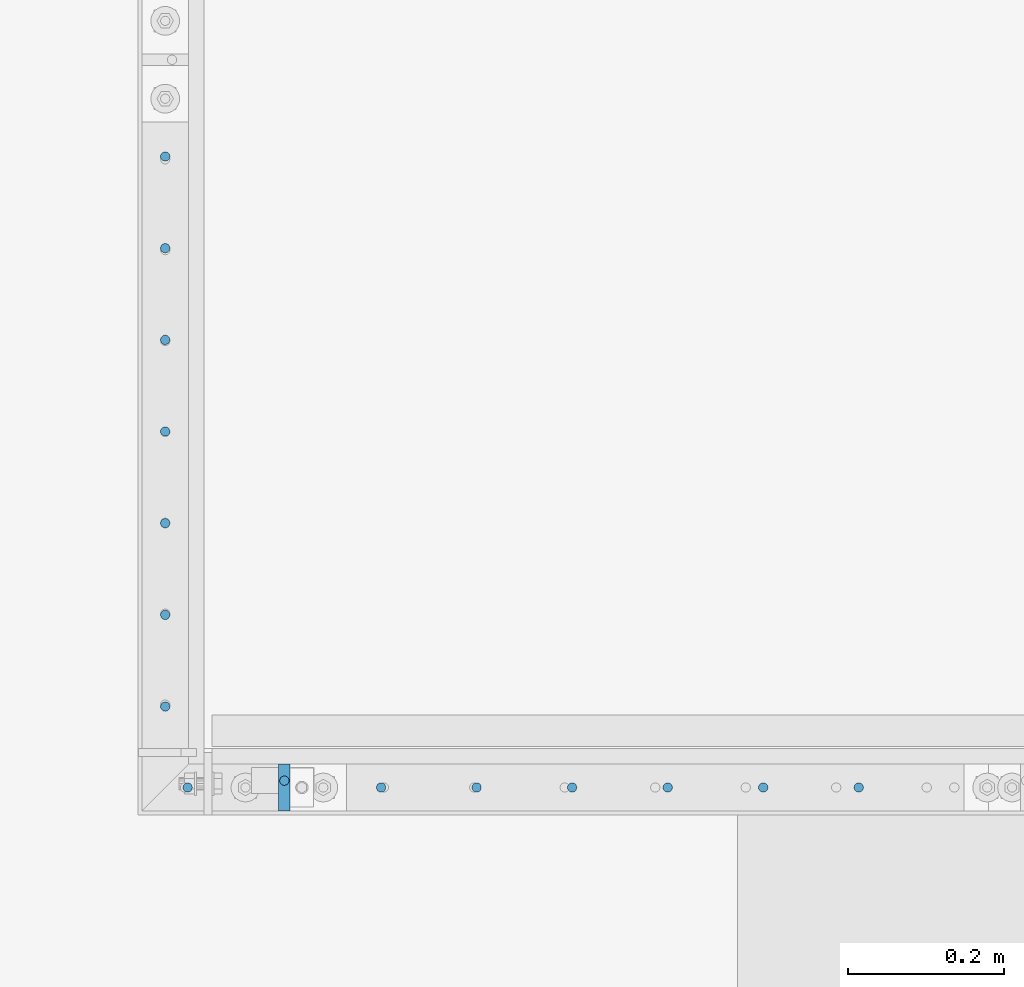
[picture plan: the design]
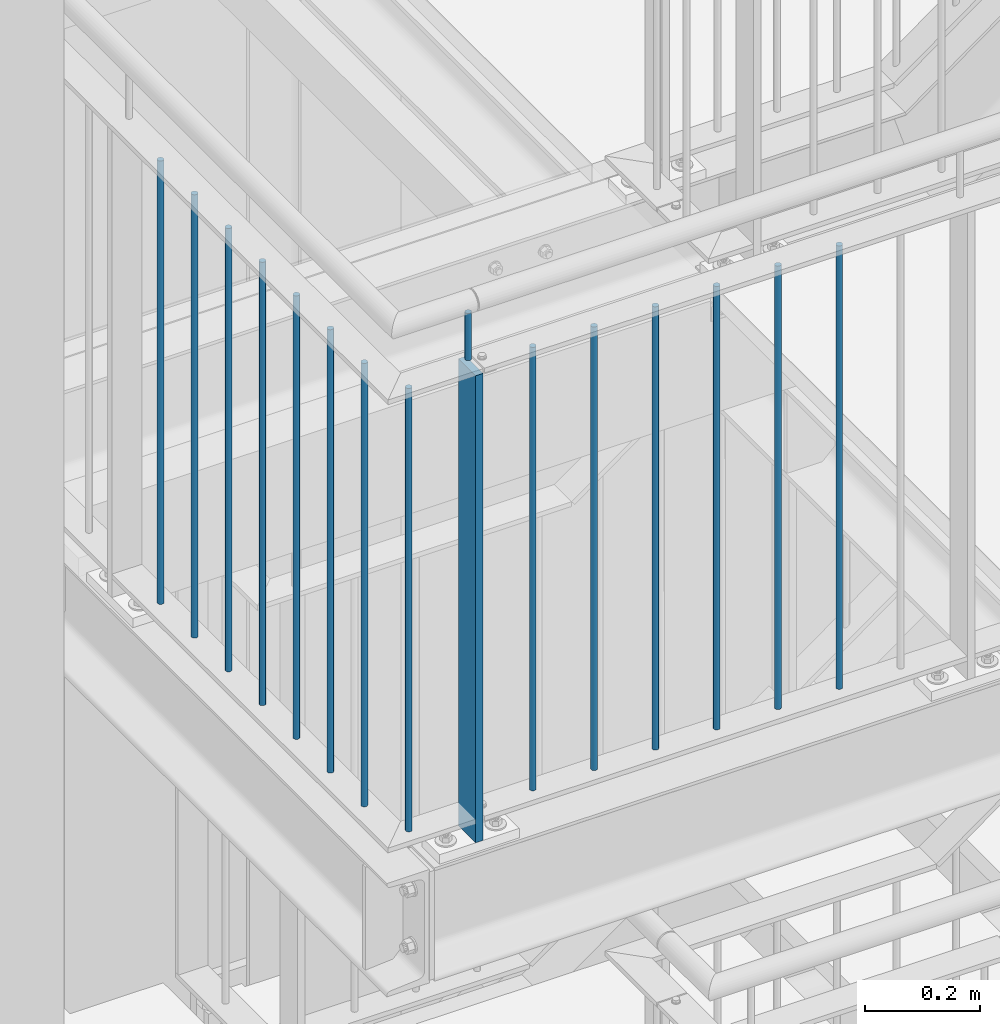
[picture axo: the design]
# One storey, part 7 of 831: 16 columns.
"""IFC2X3 building model written with IfcOpenShell, lengths in millimetres."""

from ifc_helpers import new_model, entity, si_unit, converted_unit, frame, origin, origin_with_axes, origin_2d, place, context, project, spatial, rectangle, circle, extrude, clip, halfspace, material, element, save


model = new_model("IFC2X3")

# Units and contexts
model_context = context("Model", 3, precision=1e-09, world=origin_with_axes())
ifc_project = project(units=[si_unit("LENGTHUNIT", "METRE", prefix="MILLI"), si_unit("AREAUNIT", "SQUARE_METRE"), si_unit("VOLUMEUNIT", "CUBIC_METRE"), converted_unit("PLANEANGLEUNIT", "DEGREE", entity("IfcPlaneAngleMeasure", 0.01745329), si_unit("PLANEANGLEUNIT", "RADIAN"), dimensions=[0, 0, 0, 0, 0, 0, 0])], contexts=[model_context])

# Site, building, storey
site_placement = place(None, origin_with_axes())
site = spatial("IfcSite", under=ifc_project, at=site_placement, CompositionType="ELEMENT")
building_placement = place(site_placement, origin_with_axes())
building = spatial("IfcBuilding", under=site, at=building_placement, Name="1", CompositionType="ELEMENT")
storey_placement = place(building_placement, origin_with_axes())
storey = spatial("IfcBuildingStorey", under=building, at=storey_placement, Name="Default Storey", CompositionType="ELEMENT", Elevation=0.0)

# Columns
ifc_material = material(Name="S235JR")
column_1_placement = place(None, frame((4162.791664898, 4526.736971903, 10974.285281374), z_axis=(0.0, 0.0, 1.0), x_axis=(-1.0, 0.0, 0.0)))
element("IfcColumn", 1, at=column_1_placement, inside=storey, material=ifc_material, Name="Railing_Picket_Landing#84", ObjectType="Railing_Picket_Landing#84", context=model_context, shape_type="Clipping", body=[
    clip(clip(extrude(circle(Radius=6.0, at=origin_2d()), origin(), (0.0, 0.0, -1.0), 965.770562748), halfspace(frame((4162.791664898, 4526.736971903, -13.486281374), z_axis=(0.0, 0.0, -1.0), x_axis=(1.0, 0.0, 0.0)), True)), halfspace(frame((4162.791664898, 4526.736971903, -952.284281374), z_axis=(0.0, 0.0, 1.0), x_axis=(-1.0, 0.0, 0.0)), True)),
])
column_2_placement = place(None, frame((4040.041641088, 4526.736971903, 10974.285281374), z_axis=(0.0, 0.0, 1.0), x_axis=(-1.0, 0.0, 0.0)))
element("IfcColumn", 2, at=column_2_placement, inside=storey, material=ifc_material, Name="Railing_Picket_Landing#85", ObjectType="Railing_Picket_Landing#85", context=model_context, shape_type="Clipping", body=[
    clip(clip(extrude(circle(Radius=6.0, at=origin_2d()), origin(), (0.0, 0.0, -1.0), 965.770562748), halfspace(frame((4040.041641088, 4526.736971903, -13.486281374), z_axis=(0.0, 0.0, -1.0), x_axis=(1.0, 0.0, 0.0)), True)), halfspace(frame((4040.041641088, 4526.736971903, -952.284281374), z_axis=(0.0, 0.0, 1.0), x_axis=(-1.0, 0.0, 0.0)), True)),
])
column_3_placement = place(None, frame((3917.291617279, 4526.736971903, 10974.285281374), z_axis=(0.0, 0.0, 1.0), x_axis=(-1.0, 0.0, 0.0)))
element("IfcColumn", 3, at=column_3_placement, inside=storey, material=ifc_material, Name="Railing_Picket_Landing#86", ObjectType="Railing_Picket_Landing#86", context=model_context, shape_type="Clipping", body=[
    clip(clip(extrude(circle(Radius=6.0, at=origin_2d()), origin(), (0.0, 0.0, -1.0), 965.770562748), halfspace(frame((3917.291617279, 4526.736971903, -13.486281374), z_axis=(0.0, 0.0, -1.0), x_axis=(1.0, 0.0, 0.0)), True)), halfspace(frame((3917.291617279, 4526.736971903, -952.284281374), z_axis=(0.0, 0.0, 1.0), x_axis=(-1.0, 0.0, 0.0)), True)),
])
column_4_placement = place(None, frame((3794.541593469, 4526.736971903, 10974.285281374), z_axis=(0.0, 0.0, 1.0), x_axis=(-1.0, 0.0, 0.0)))
element("IfcColumn", 4, at=column_4_placement, inside=storey, material=ifc_material, Name="Railing_Picket_Landing#87", ObjectType="Railing_Picket_Landing#87", context=model_context, shape_type="Clipping", body=[
    clip(clip(extrude(circle(Radius=6.0, at=origin_2d()), origin(), (0.0, 0.0, -1.0), 965.770562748), halfspace(frame((3794.541593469, 4526.736971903, -13.486281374), z_axis=(0.0, 0.0, -1.0), x_axis=(1.0, 0.0, 0.0)), True)), halfspace(frame((3794.541593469, 4526.736971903, -952.284281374), z_axis=(0.0, 0.0, 1.0), x_axis=(-1.0, 0.0, 0.0)), True)),
])
column_5_placement = place(None, frame((3671.79156966, 4526.736971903, 10974.285281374), z_axis=(0.0, 0.0, 1.0), x_axis=(-1.0, 0.0, 0.0)))
element("IfcColumn", 5, at=column_5_placement, inside=storey, material=ifc_material, Name="Railing_Picket_Landing#88", ObjectType="Railing_Picket_Landing#88", context=model_context, shape_type="Clipping", body=[
    clip(clip(extrude(circle(Radius=6.0, at=origin_2d()), origin(), (0.0, 0.0, -1.0), 965.770562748), halfspace(frame((3671.79156966, 4526.736971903, -13.486281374), z_axis=(0.0, 0.0, -1.0), x_axis=(1.0, 0.0, 0.0)), True)), halfspace(frame((3671.79156966, 4526.736971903, -952.284281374), z_axis=(0.0, 0.0, 1.0), x_axis=(-1.0, 0.0, 0.0)), True)),
])
column_6_placement = place(None, frame((3549.04154585, 4526.736971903, 10974.285281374), z_axis=(0.0, 0.0, 1.0), x_axis=(-1.0, 0.0, 0.0)))
element("IfcColumn", 6, at=column_6_placement, inside=storey, material=ifc_material, Name="Railing_Picket_Landing#89", ObjectType="Railing_Picket_Landing#89", context=model_context, shape_type="Clipping", body=[
    clip(clip(extrude(circle(Radius=6.0, at=origin_2d()), origin(), (0.0, 0.0, -1.0), 965.770562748), halfspace(frame((3549.04154585, 4526.736971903, -13.486281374), z_axis=(0.0, 0.0, -1.0), x_axis=(1.0, 0.0, 0.0)), True)), halfspace(frame((3549.04154585, 4526.736971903, -952.284281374), z_axis=(0.0, 0.0, 1.0), x_axis=(-1.0, 0.0, 0.0)), True)),
])
column_7_placement = place(None, frame((3300.54154585, 4526.736971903, 10974.285281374), z_axis=(0.0, 0.0, 1.0), x_axis=(-1.0, 0.0, 0.0)))
element("IfcColumn", 7, at=column_7_placement, inside=storey, material=ifc_material, Name="Railing_Picket_Landing#90", ObjectType="Railing_Picket_Landing#90", context=model_context, shape_type="Clipping", body=[
    clip(clip(extrude(circle(Radius=6.0, at=origin_2d()), origin(), (0.0, 0.0, -1.0), 965.770562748), halfspace(frame((3300.54154585, 4526.736971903, -13.486281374), z_axis=(0.0, 0.0, -1.0), x_axis=(1.0, 0.0, 0.0)), True)), halfspace(frame((3300.54154585, 4526.736971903, -952.284281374), z_axis=(0.0, 0.0, 1.0), x_axis=(-1.0, 0.0, 0.0)), True)),
])
column_8_placement = place(None, frame((3271.713402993, 4630.705992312, 10974.285281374), z_axis=(0.0, 0.0, 1.0), x_axis=(0.0, 1.0, 0.0)))
element("IfcColumn", 8, at=column_8_placement, inside=storey, material=ifc_material, Name="Railing_Picket_Landing#91", ObjectType="Railing_Picket_Landing#91", context=model_context, shape_type="Clipping", body=[
    clip(clip(extrude(circle(Radius=6.0, at=origin_2d()), origin(), (0.0, 0.0, -1.0), 965.770562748), halfspace(frame((-4630.705992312, 3271.713402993, -13.486281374), z_axis=(0.0, 0.0, -1.0), x_axis=(0.0, 1.0, 0.0)), True)), halfspace(frame((-4630.705992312, 3271.713402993, -952.284281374), z_axis=(0.0, 0.0, 1.0), x_axis=(0.0, -1.0, 0.0)), True)),
])
column_9_placement = place(None, frame((3271.713402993, 4748.503155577, 10974.285281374), z_axis=(0.0, 0.0, 1.0), x_axis=(0.0, 1.0, 0.0)))
element("IfcColumn", 9, at=column_9_placement, inside=storey, material=ifc_material, Name="Railing_Picket_Landing#92", ObjectType="Railing_Picket_Landing#92", context=model_context, shape_type="Clipping", body=[
    clip(clip(extrude(circle(Radius=6.0, at=origin_2d()), origin(), (0.0, 0.0, -1.0), 965.770562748), halfspace(frame((-4748.503155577, 3271.713402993, -13.486281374), z_axis=(0.0, 0.0, -1.0), x_axis=(0.0, 1.0, 0.0)), True)), halfspace(frame((-4748.503155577, 3271.713402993, -952.284281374), z_axis=(0.0, 0.0, 1.0), x_axis=(0.0, -1.0, 0.0)), True)),
])
column_10_placement = place(None, frame((3271.713402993, 4866.300318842, 10974.285281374), z_axis=(0.0, 0.0, 1.0), x_axis=(0.0, 1.0, 0.0)))
element("IfcColumn", 10, at=column_10_placement, inside=storey, material=ifc_material, Name="Railing_Picket_Landing#93", ObjectType="Railing_Picket_Landing#93", context=model_context, shape_type="Clipping", body=[
    clip(clip(extrude(circle(Radius=6.0, at=origin_2d()), origin(), (0.0, 0.0, -1.0), 965.770562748), halfspace(frame((-4866.300318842, 3271.713402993, -13.486281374), z_axis=(0.0, 0.0, -1.0), x_axis=(0.0, 1.0, 0.0)), True)), halfspace(frame((-4866.300318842, 3271.713402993, -952.284281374), z_axis=(0.0, 0.0, 1.0), x_axis=(0.0, -1.0, 0.0)), True)),
])
column_11_placement = place(None, frame((3271.713402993, 4984.097482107, 10974.285281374), z_axis=(0.0, 0.0, 1.0), x_axis=(0.0, 1.0, 0.0)))
element("IfcColumn", 11, at=column_11_placement, inside=storey, material=ifc_material, Name="Railing_Picket_Landing#94", ObjectType="Railing_Picket_Landing#94", context=model_context, shape_type="Clipping", body=[
    clip(clip(extrude(circle(Radius=6.0, at=origin_2d()), origin(), (0.0, 0.0, -1.0), 965.770562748), halfspace(frame((-4984.097482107, 3271.713402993, -13.486281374), z_axis=(0.0, 0.0, -1.0), x_axis=(0.0, 1.0, 0.0)), True)), halfspace(frame((-4984.097482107, 3271.713402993, -952.284281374), z_axis=(0.0, 0.0, 1.0), x_axis=(0.0, -1.0, 0.0)), True)),
])
column_12_placement = place(None, frame((3271.713402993, 5101.894645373, 10974.285281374), z_axis=(0.0, 0.0, 1.0), x_axis=(0.0, 1.0, 0.0)))
element("IfcColumn", 12, at=column_12_placement, inside=storey, material=ifc_material, Name="Railing_Picket_Landing#95", ObjectType="Railing_Picket_Landing#95", context=model_context, shape_type="Clipping", body=[
    clip(clip(extrude(circle(Radius=6.0, at=origin_2d()), origin(), (0.0, 0.0, -1.0), 965.770562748), halfspace(frame((-5101.894645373, 3271.713402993, -13.486281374), z_axis=(0.0, 0.0, -1.0), x_axis=(0.0, 1.0, 0.0)), True)), halfspace(frame((-5101.894645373, 3271.713402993, -952.284281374), z_axis=(0.0, 0.0, 1.0), x_axis=(0.0, -1.0, 0.0)), True)),
])
column_13_placement = place(None, frame((3271.713402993, 5219.691808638, 10974.285281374), z_axis=(0.0, 0.0, 1.0), x_axis=(0.0, 1.0, 0.0)))
element("IfcColumn", 13, at=column_13_placement, inside=storey, material=ifc_material, Name="Railing_Picket_Landing#96", ObjectType="Railing_Picket_Landing#96", context=model_context, shape_type="Clipping", body=[
    clip(clip(extrude(circle(Radius=6.0, at=origin_2d()), origin(), (0.0, 0.0, -1.0), 965.770562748), halfspace(frame((-5219.691808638, 3271.713402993, -13.486281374), z_axis=(0.0, 0.0, -1.0), x_axis=(0.0, 1.0, 0.0)), True)), halfspace(frame((-5219.691808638, 3271.713402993, -952.284281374), z_axis=(0.0, 0.0, 1.0), x_axis=(0.0, -1.0, 0.0)), True)),
])
column_14_placement = place(None, frame((3271.713402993, 5337.488971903, 10974.285281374), z_axis=(0.0, 0.0, 1.0), x_axis=(0.0, 1.0, 0.0)))
element("IfcColumn", 14, at=column_14_placement, inside=storey, material=ifc_material, Name="Railing_Picket_Landing#97", ObjectType="Railing_Picket_Landing#97", context=model_context, shape_type="Clipping", body=[
    clip(clip(extrude(circle(Radius=6.0, at=origin_2d()), origin(), (0.0, 0.0, -1.0), 965.770562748), halfspace(frame((-5337.488971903, 3271.713402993, -13.486281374), z_axis=(0.0, 0.0, -1.0), x_axis=(0.0, 1.0, 0.0)), True)), halfspace(frame((-5337.488971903, 3271.713402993, -952.284281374), z_axis=(0.0, 0.0, 1.0), x_axis=(0.0, -1.0, 0.0)), True)),
])
column_15_placement = place(None, frame((3424.79154585, 4535.536971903, 11079.285281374), z_axis=(0.0, 0.0, 1.0), x_axis=(0.0, 1.0, 0.0)))
element("IfcColumn", 15, at=column_15_placement, inside=storey, material=ifc_material, Name="Bar#13", ObjectType="Bar#13", context=model_context, shape_type="Clipping", body=[
    clip(clip(extrude(circle(Radius=6.0, at=origin_2d()), origin(), (0.0, 0.0, -1.0), 116.970562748), halfspace(frame((-4535.536971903, 3424.79154585, -8.486281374), z_axis=(0.0, 0.0, -1.0), x_axis=(0.0, 1.0, 0.0)), True)), halfspace(frame((-4535.536971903, 3424.79154585, -108.484281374), z_axis=(0.0, 0.0, 1.0), x_axis=(0.0, -1.0, 0.0)), True)),
])
column_16_placement = place(None, frame((3424.79154585, 4526.736971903, 10991.723292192), z_axis=(0.0, 0.0, 1.0), x_axis=(-1.0, 0.0, 0.0)))
element("IfcColumn", 16, at=column_16_placement, inside=storey, material=ifc_material, Name="Railing_Post_Landing#13", ObjectType="Railing_Post_Landing#13", context=model_context, shape_type="Clipping", body=[
    clip(clip(extrude(rectangle(XDim=15.0, YDim=60.0, at=origin_2d()), origin(), (0.0, 0.0, -1.0), 1070.646584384), halfspace(frame((3424.79154585, 4526.736971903, -1019.722292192), z_axis=(0.0, 0.0, 1.0), x_axis=(-1.0, 0.0, 0.0)), True)), halfspace(frame((3424.79154585, 4526.736971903, -30.924292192), z_axis=(0.0, 0.0, -1.0), x_axis=(1.0, 0.0, 0.0)), True)),
])

save(model, "model.ifc")
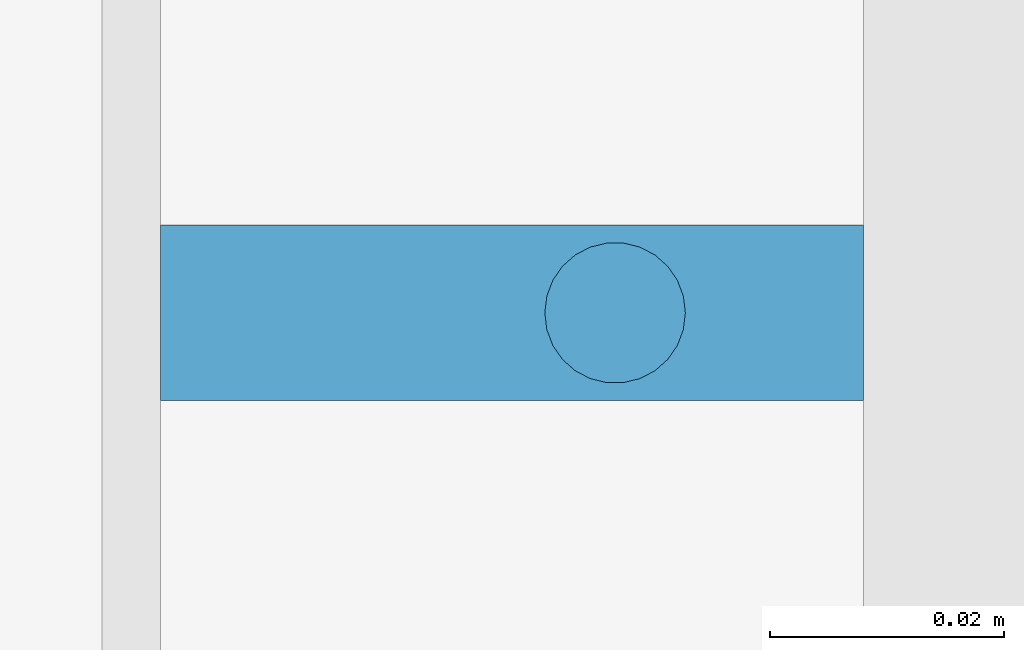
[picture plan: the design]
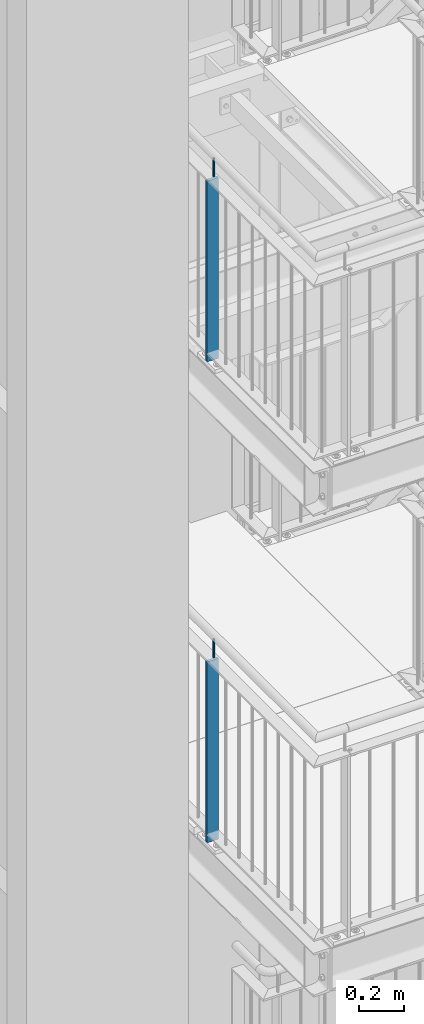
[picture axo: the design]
# One storey, part 18 of 831: 4 columns.
"""IFC2X3 building model written with IfcOpenShell, lengths in millimetres."""

import ifcopenshell
import ifcopenshell.guid

model = None  # the IFC model being written
_history = None  # IfcOwnerHistory: only IFC2X3 demands one
_inside = {}  # id of a spatial element -> (the spatial element, [elements in it])
_under = {}  # id of a project, library or spatial element -> (it, [spatial elements below it])
_declared = {}  # id of a project -> (the project, [libraries it declares])
_typed = {}  # id of a type object -> (the type object, [elements of that type])
_made_of = {}  # id of a material, layer set ... -> (it, [elements and type objects made of it])


def new_model(schema):
    """Start an empty IFC model of exactly this schema.

    Asked for "IFC4X3", IfcOpenShell would pick the latest addendum, in which some entities
    have other attributes; the version numbers below select the first issue.
    IFC2X3 requires an IfcOwnerHistory on every rooted entity: one is made here for all.
    """
    global model, _history
    if schema == "IFC4X3":
        model = ifcopenshell.file(schema_version=(4, 3, 0, 0))
    else:
        model = ifcopenshell.file(schema=schema)
    _inside.clear()
    _under.clear()
    _declared.clear()
    _typed.clear()
    _made_of.clear()
    _history = None
    if model.schema == "IFC2X3":
        org = make("IfcOrganization", Name="unknown")
        user = make(
            "IfcPersonAndOrganization",
            ThePerson=make("IfcPerson", FamilyName="unknown"),
            TheOrganization=org,
        )
        app = make(
            "IfcApplication",
            ApplicationDeveloper=org,
            Version="unknown",
            ApplicationFullName="unknown",
            ApplicationIdentifier="unknown",
        )
        _history = make(
            "IfcOwnerHistory",
            OwningUser=user,
            OwningApplication=app,
            ChangeAction="ADDED",
            CreationDate=0,
        )
    return model


def make(cls, **values):
    """One entity of the class cls with the attributes given. An attribute that is None is left unset."""
    return model.create_entity(
        cls, **{name: value for name, value in values.items() if value is not None}
    )


def entity(cls, *values):
    """Any entity or typed value of the class cls, its attributes in the order of the schema. None: left unset."""
    e = model.create_entity(cls)
    for i, value in enumerate(values):
        if value is not None:
            e[i] = value
    return e


def rooted(cls, **values):
    """An entity with a GlobalId (a new one), such as an element, a storey or a relation."""
    return make(cls, GlobalId=ifcopenshell.guid.new(), OwnerHistory=_history, **values)


def si_unit(unit_type, name, prefix=None):
    """IfcSIUnit, for example si_unit("LENGTHUNIT", "METRE", prefix="MILLI")."""
    return make("IfcSIUnit", UnitType=unit_type, Prefix=prefix, Name=name)


def converted_unit(unit_type, name, factor, base, dimensions=None, offset=None):
    """IfcConversionBasedUnit, such as the inch: factor (a typed value) times the base unit."""
    return make(
        "IfcConversionBasedUnit"
        if offset is None
        else "IfcConversionBasedUnitWithOffset",
        ConversionOffset=offset,
        Dimensions=None
        if dimensions is None
        else entity("IfcDimensionalExponents", *dimensions),
        UnitType=unit_type,
        Name=name,
        ConversionFactor=make(
            "IfcMeasureWithUnit", ValueComponent=factor, UnitComponent=base
        ),
    )


def assignment(units):
    """IfcUnitAssignment: the units of a project."""
    return None if units is None else make("IfcUnitAssignment", Units=units)


def point(xyz):
    """IfcCartesianPoint."""
    return None if xyz is None else make("IfcCartesianPoint", Coordinates=xyz)


def direction(xyz):
    """IfcDirection."""
    return None if xyz is None else make("IfcDirection", DirectionRatios=xyz)


def frame(location, z_axis=None, x_axis=None):
    """IfcAxis2Placement3D, a coordinate frame: its origin and axes. An axis left out is left unset."""
    return make(
        "IfcAxis2Placement3D",
        Location=point(location),
        Axis=direction(z_axis),
        RefDirection=direction(x_axis),
    )


def frame_2d(location, x_axis=None):
    """IfcAxis2Placement2D, a coordinate frame in the plane: its origin and x axis."""
    return make(
        "IfcAxis2Placement2D", Location=point(location), RefDirection=direction(x_axis)
    )


def origin():
    """The frame at (0, 0, 0) with its axes left unset."""
    return frame((0.0, 0.0, 0.0))


def origin_with_axes():
    """The frame at (0, 0, 0) with the z axis (0, 0, 1) and the x axis (1, 0, 0) written out."""
    return frame((0.0, 0.0, 0.0), z_axis=(0.0, 0.0, 1.0), x_axis=(1.0, 0.0, 0.0))


def origin_2d():
    """The frame at (0, 0) in the plane with its x axis left unset."""
    return frame_2d((0.0, 0.0))


def place(relative_to, where):
    """IfcLocalPlacement: puts the frame where relative to a parent placement (None: the world)."""
    return make(
        "IfcLocalPlacement", PlacementRelTo=relative_to, RelativePlacement=where
    )


def context(
    kind, dimensions, precision=None, world=None, true_north=None, identifier=None
):
    """IfcGeometricRepresentationContext, for example the 3D "Model" context."""
    return make(
        "IfcGeometricRepresentationContext",
        ContextIdentifier=identifier,
        ContextType=kind,
        CoordinateSpaceDimension=dimensions,
        Precision=precision,
        WorldCoordinateSystem=world,
        TrueNorth=true_north,
    )


def project(units=None, contexts=None):
    """IfcProject with its units and contexts."""
    return rooted(
        "IfcProject",
        Name="project",
        RepresentationContexts=contexts,
        UnitsInContext=assignment(units),
    )


def spatial(cls, under=None, at=None, **own):
    """A site, building, storey or space (cls), placed at a placement, below another one or the project."""
    s = rooted(cls, ObjectPlacement=at, **own)
    if under is not None:
        _under.setdefault(under.id(), (under, []))[1].append(s)
    return s


def profile(cls, at=None, kind="AREA", **sizes):
    """A parametric profile (cls). Its sizes go by their IFC names, for example OverallWidth=200.0."""
    return make(cls, ProfileType=kind, Position=at, **sizes)


def rectangle(**sizes):
    """IfcRectangleProfileDef."""
    return profile("IfcRectangleProfileDef", **sizes)


def circle(**sizes):
    """IfcCircleProfileDef."""
    return profile("IfcCircleProfileDef", **sizes)


def extrude(swept, where, along, depth):
    """IfcExtrudedAreaSolid: the profile swept, set in the frame where, extruded along a direction by depth."""
    return make(
        "IfcExtrudedAreaSolid",
        SweptArea=swept,
        Position=where,
        ExtrudedDirection=direction(along),
        Depth=depth,
    )


def clip(a, b, op="DIFFERENCE"):
    """IfcBooleanClippingResult: the solid a cut by the half space b."""
    return make(
        "IfcBooleanClippingResult", Operator=op, FirstOperand=a, SecondOperand=b
    )


def halfspace(plane, agree):
    """IfcHalfSpaceSolid: all space on one side of the plane z = 0 of the frame plane."""
    return make(
        "IfcHalfSpaceSolid",
        BaseSurface=make("IfcPlane", Position=plane),
        AgreementFlag=agree,
    )


def shape(context_of_items, identifier, shape_type, items):
    """IfcShapeRepresentation: the items that make up one representation, for example the "Body"."""
    return make(
        "IfcShapeRepresentation",
        ContextOfItems=context_of_items,
        RepresentationIdentifier=identifier,
        RepresentationType=shape_type,
        Items=items,
    )


def material(Name=None, Category=None):
    """IfcMaterial."""
    return make("IfcMaterial", Name=Name, Category=Category)


def made_of(thing, what):
    """Note that an element or type object is made of a material, layer set ...; save() writes the relation."""
    if what is not None:
        _made_of.setdefault(what.id(), (what, []))[1].append(thing)
    return thing


def element(
    cls,
    number,
    at=None,
    inside=None,
    cuts=None,
    type_object=None,
    material=None,
    context=None,
    identifier="Body",
    shape_type=None,
    held_by="IfcProductDefinitionShape",
    body=None,
    shapes=None,
    **own,
):
    """One element of the class cls, such as IfcWall. Its Tag is "e" and its number.

    at: its placement. inside: the storey or other place that contains it. cuts: it is an
    opening in that element (IfcRelVoidsElement). A single representation is given by context,
    identifier, shape_type and body (its items); several are given by shapes. held_by: the class
    of the entity that holds the representations. save() writes the other relations.
    """
    e = rooted(cls, Tag="e%d" % number, ObjectPlacement=at, **own)
    if body is not None:
        shapes = [shape(context, identifier, shape_type, body)]
    if shapes is not None:
        e.Representation = make(held_by, Representations=shapes)
    if inside is not None:
        _inside.setdefault(inside.id(), (inside, []))[1].append(e)
    if cuts is not None:
        rooted(
            "IfcRelVoidsElement", RelatingBuildingElement=cuts, RelatedOpeningElement=e
        )
    if type_object is not None:
        _typed.setdefault(type_object.id(), (type_object, []))[1].append(e)
    return made_of(e, material)


def aggregate(whole, parts):
    """IfcRelAggregates: a whole, such as a stair, and the parts it consists of."""
    return rooted("IfcRelAggregates", RelatingObject=whole, RelatedObjects=parts)


def save(model, path):
    """Write the relations noted so far, then the file.

    IfcRelAggregates (storeys below a building ...), IfcRelContainedInSpatialStructure (elements
    in a storey), IfcRelDefinesByType, IfcRelAssociatesMaterial and IfcRelDeclares: one each for
    every whole, place, type object, material and project.
    """
    for whole, parts in _under.values():
        aggregate(whole, parts)
    for where, things in _inside.values():
        rooted(
            "IfcRelContainedInSpatialStructure",
            RelatedElements=things,
            RelatingStructure=where,
        )
    for kind, things in _typed.values():
        rooted("IfcRelDefinesByType", RelatedObjects=things, RelatingType=kind)
    for what, things in _made_of.values():
        rooted("IfcRelAssociatesMaterial", RelatedObjects=things, RelatingMaterial=what)
    for by, libraries in _declared.values():
        rooted("IfcRelDeclares", RelatingContext=by, RelatedDefinitions=libraries)
    model.write(path)


model = new_model("IFC2X3")

# Units and contexts
model_context = context("Model", 3, precision=1e-09, world=origin_with_axes())
ifc_project = project(units=[si_unit("LENGTHUNIT", "METRE", prefix="MILLI"), si_unit("AREAUNIT", "SQUARE_METRE"), si_unit("VOLUMEUNIT", "CUBIC_METRE"), converted_unit("PLANEANGLEUNIT", "DEGREE", entity("IfcPlaneAngleMeasure", 0.01745329), si_unit("PLANEANGLEUNIT", "RADIAN"), dimensions=[0, 0, 0, 0, 0, 0, 0])], contexts=[model_context])

# Site, building, storey
site_placement = place(None, origin_with_axes())
site = spatial("IfcSite", under=ifc_project, at=site_placement, CompositionType="ELEMENT")
building_placement = place(site_placement, origin_with_axes())
building = spatial("IfcBuilding", under=site, at=building_placement, Name="1", CompositionType="ELEMENT")
storey_placement = place(building_placement, origin_with_axes())
storey = spatial("IfcBuildingStorey", under=building, at=storey_placement, Name="Default Storey", CompositionType="ELEMENT", Elevation=0.0)

# Columns
ifc_material = material(Name="S235JR")
column_1_placement = place(None, frame((3271.713402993, 5461.738971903, 8359.723292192), z_axis=(0.0, 0.0, 1.0), x_axis=(0.0, 1.0, 0.0)))
element("IfcColumn", 1, at=column_1_placement, inside=storey, material=ifc_material, Name="Railing_Post_Landing#14", ObjectType="Railing_Post_Landing#14", context=model_context, shape_type="Clipping", body=[
    clip(clip(extrude(rectangle(XDim=15.0, YDim=60.0, at=origin_2d()), origin(), (0.0, 0.0, -1.0), 1070.646584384), halfspace(frame((-5461.738971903, 3271.713402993, -1019.722292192), z_axis=(0.0, 0.0, 1.0), x_axis=(0.0, -1.0, 0.0)), True)), halfspace(frame((-5461.738971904, 3271.713402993, -30.924292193), z_axis=(0.0, 0.0, -1.0), x_axis=(0.0, 1.0, 0.0)), True)),
])
for number, where, z_axis, x_axis, name in (
    (2, (3280.513402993, 5461.738971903, 8447.285281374), (0.0, 0.0, 1.0), (1.0, 0.0, 0.0), "Bar#14"),
    (3, (3280.513402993, 5461.738971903, 11079.285281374), (0.0, 0.0, 1.0), (1.0, 0.0, 0.0), "Bar#14"),
):
    element("IfcColumn", number, at=place(None, frame(where, z_axis=z_axis, x_axis=x_axis)), inside=storey, material=ifc_material, Name=name, ObjectType="Bar#14", context=model_context, shape_type="Clipping", body=[
        clip(clip(extrude(circle(Radius=6.0, at=origin_2d()), origin(), (0.0, 0.0, -1.0), 116.970562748), halfspace(frame((-3280.513402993, -5461.738971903, -8.486281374), z_axis=(0.0, 0.0, -1.0), x_axis=(-1.0, 0.0, 0.0)), True)), halfspace(frame((-3280.513402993, -5461.738971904, -108.484281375), z_axis=(0.0, 0.0, 1.0), x_axis=(1.0, 0.0, 0.0)), True)),
    ])
column_2_placement = place(None, frame((3271.713402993, 5461.738971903, 10991.723292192), z_axis=(0.0, 0.0, 1.0), x_axis=(0.0, 1.0, 0.0)))
element("IfcColumn", 4, at=column_2_placement, inside=storey, material=ifc_material, Name="Railing_Post_Landing#14", ObjectType="Railing_Post_Landing#14", context=model_context, shape_type="Clipping", body=[
    clip(clip(extrude(rectangle(XDim=15.0, YDim=60.0, at=origin_2d()), origin(), (0.0, 0.0, -1.0), 1070.646584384), halfspace(frame((-5461.738971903, 3271.713402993, -1019.722292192), z_axis=(0.0, 0.0, 1.0), x_axis=(0.0, -1.0, 0.0)), True)), halfspace(frame((-5461.738971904, 3271.713402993, -30.924292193), z_axis=(0.0, 0.0, -1.0), x_axis=(0.0, 1.0, 0.0)), True)),
])

save(model, "model.ifc")
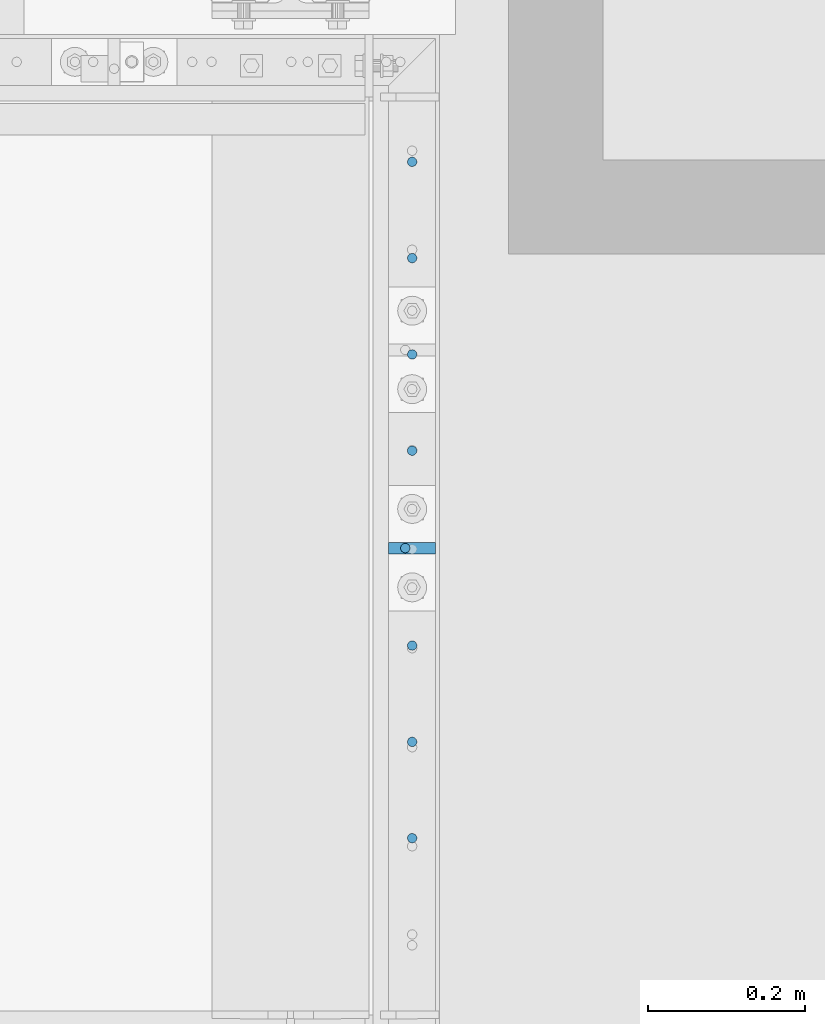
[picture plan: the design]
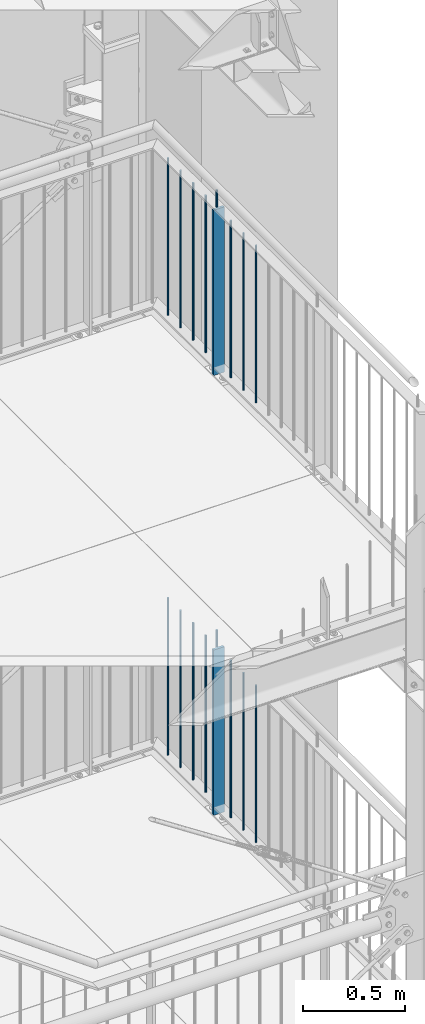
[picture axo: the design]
# One storey, part 105 of 831: 18 columns.
"""IFC2X3 building model written with IfcOpenShell, lengths in millimetres."""

from ifc_helpers import new_model, entity, si_unit, converted_unit, frame, origin, origin_with_axes, origin_2d, place, context, project, spatial, rectangle, circle, extrude, clip, halfspace, material, element, save


model = new_model("IFC2X3")

# Units and contexts
model_context = context("Model", 3, precision=1e-09, world=origin_with_axes())
ifc_project = project(units=[si_unit("LENGTHUNIT", "METRE", prefix="MILLI"), si_unit("AREAUNIT", "SQUARE_METRE"), si_unit("VOLUMEUNIT", "CUBIC_METRE"), converted_unit("PLANEANGLEUNIT", "DEGREE", entity("IfcPlaneAngleMeasure", 0.01745329), si_unit("PLANEANGLEUNIT", "RADIAN"), dimensions=[0, 0, 0, 0, 0, 0, 0])], contexts=[model_context])

# Site, building, storey
site_placement = place(None, origin_with_axes())
site = spatial("IfcSite", under=ifc_project, at=site_placement, CompositionType="ELEMENT")
building_placement = place(site_placement, origin_with_axes())
building = spatial("IfcBuilding", under=site, at=building_placement, Name="1", CompositionType="ELEMENT")
storey_placement = place(building_placement, origin_with_axes())
storey = spatial("IfcBuildingStorey", under=building, at=storey_placement, Name="Default Storey", CompositionType="ELEMENT", Elevation=0.0)

# Columns
ifc_material = material(Name="S235JR")
column_1_placement = place(None, frame((9021.713402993, 7229.236329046, 9658.285281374), z_axis=(0.0, 0.0, 1.0), x_axis=(0.0, -1.0, 0.0)))
element("IfcColumn", 1, at=column_1_placement, inside=storey, material=ifc_material, Name="Railing_Picket_Landing#31", ObjectType="Railing_Picket_Landing#31", context=model_context, shape_type="Clipping", body=[
    clip(clip(extrude(circle(Radius=6.0, at=origin_2d()), origin(), (0.0, 0.0, -1.0), 965.770562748), halfspace(frame((7229.236329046, -9021.713402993, -13.486281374), z_axis=(0.0, 0.0, -1.0), x_axis=(0.0, -1.0, 0.0)), True)), halfspace(frame((7229.236329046, -9021.713402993, -952.284281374), z_axis=(0.0, 0.0, 1.0), x_axis=(0.0, 1.0, 0.0)), True)),
])
column_2_placement = place(None, frame((9021.713402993, 7106.486305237, 9658.285281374), z_axis=(0.0, 0.0, 1.0), x_axis=(0.0, -1.0, 0.0)))
element("IfcColumn", 2, at=column_2_placement, inside=storey, material=ifc_material, Name="Railing_Picket_Landing#32", ObjectType="Railing_Picket_Landing#32", context=model_context, shape_type="Clipping", body=[
    clip(clip(extrude(circle(Radius=6.0, at=origin_2d()), origin(), (0.0, 0.0, -1.0), 965.770562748), halfspace(frame((7106.486305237, -9021.713402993, -13.486281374), z_axis=(0.0, 0.0, -1.0), x_axis=(0.0, -1.0, 0.0)), True)), halfspace(frame((7106.486305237, -9021.713402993, -952.284281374), z_axis=(0.0, 0.0, 1.0), x_axis=(0.0, 1.0, 0.0)), True)),
])
column_3_placement = place(None, frame((9021.713402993, 6983.736281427, 9658.285281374), z_axis=(0.0, 0.0, 1.0), x_axis=(0.0, -1.0, 0.0)))
element("IfcColumn", 3, at=column_3_placement, inside=storey, material=ifc_material, Name="Railing_Picket_Landing#33", ObjectType="Railing_Picket_Landing#33", context=model_context, shape_type="Clipping", body=[
    clip(clip(extrude(circle(Radius=6.0, at=origin_2d()), origin(), (0.0, 0.0, -1.0), 965.770562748), halfspace(frame((6983.736281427, -9021.713402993, -13.486281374), z_axis=(0.0, 0.0, -1.0), x_axis=(0.0, -1.0, 0.0)), True)), halfspace(frame((6983.736281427, -9021.713402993, -952.284281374), z_axis=(0.0, 0.0, 1.0), x_axis=(0.0, 1.0, 0.0)), True)),
])
column_4_placement = place(None, frame((9021.713402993, 6860.986257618, 9658.285281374), z_axis=(0.0, 0.0, 1.0), x_axis=(0.0, -1.0, 0.0)))
element("IfcColumn", 4, at=column_4_placement, inside=storey, material=ifc_material, Name="Railing_Picket_Landing#34", ObjectType="Railing_Picket_Landing#34", context=model_context, shape_type="Clipping", body=[
    clip(clip(extrude(circle(Radius=6.0, at=origin_2d()), origin(), (0.0, 0.0, -1.0), 965.770562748), halfspace(frame((6860.986257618, -9021.713402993, -13.486281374), z_axis=(0.0, 0.0, -1.0), x_axis=(0.0, -1.0, 0.0)), True)), halfspace(frame((6860.986257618, -9021.713402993, -952.284281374), z_axis=(0.0, 0.0, 1.0), x_axis=(0.0, 1.0, 0.0)), True)),
])
column_5_placement = place(None, frame((9021.713402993, 6612.486257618, 9658.285281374), z_axis=(0.0, 0.0, 1.0), x_axis=(0.0, -1.0, 0.0)))
element("IfcColumn", 5, at=column_5_placement, inside=storey, material=ifc_material, Name="Railing_Picket_Landing#35", ObjectType="Railing_Picket_Landing#35", context=model_context, shape_type="Clipping", body=[
    clip(clip(extrude(circle(Radius=6.0, at=origin_2d()), origin(), (0.0, 0.0, -1.0), 965.770562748), halfspace(frame((6612.486257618, -9021.713402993, -13.486281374), z_axis=(0.0, 0.0, -1.0), x_axis=(0.0, -1.0, 0.0)), True)), halfspace(frame((6612.486257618, -9021.713402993, -952.284281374), z_axis=(0.0, 0.0, 1.0), x_axis=(0.0, 1.0, 0.0)), True)),
])
column_6_placement = place(None, frame((9021.713402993, 6489.736233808, 9658.285281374), z_axis=(0.0, 0.0, 1.0), x_axis=(0.0, -1.0, 0.0)))
element("IfcColumn", 6, at=column_6_placement, inside=storey, material=ifc_material, Name="Railing_Picket_Landing#36", ObjectType="Railing_Picket_Landing#36", context=model_context, shape_type="Clipping", body=[
    clip(clip(extrude(circle(Radius=6.0, at=origin_2d()), origin(), (0.0, 0.0, -1.0), 965.770562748), halfspace(frame((6489.736233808, -9021.713402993, -13.486281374), z_axis=(0.0, 0.0, -1.0), x_axis=(0.0, -1.0, 0.0)), True)), halfspace(frame((6489.736233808, -9021.713402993, -952.284281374), z_axis=(0.0, 0.0, 1.0), x_axis=(0.0, 1.0, 0.0)), True)),
])
column_7_placement = place(None, frame((9021.713402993, 6366.986209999, 9658.285281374), z_axis=(0.0, 0.0, 1.0), x_axis=(0.0, -1.0, 0.0)))
element("IfcColumn", 7, at=column_7_placement, inside=storey, material=ifc_material, Name="Railing_Picket_Landing#37", ObjectType="Railing_Picket_Landing#37", context=model_context, shape_type="Clipping", body=[
    clip(clip(extrude(circle(Radius=6.0, at=origin_2d()), origin(), (0.0, 0.0, -1.0), 965.770562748), halfspace(frame((6366.986209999, -9021.713402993, -13.486281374), z_axis=(0.0, 0.0, -1.0), x_axis=(0.0, -1.0, 0.0)), True)), halfspace(frame((6366.986209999, -9021.713402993, -952.284281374), z_axis=(0.0, 0.0, 1.0), x_axis=(0.0, 1.0, 0.0)), True)),
])
column_8_placement = place(None, frame((9012.913402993, 6736.736257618, 9763.285281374), z_axis=(0.0, 0.0, 1.0), x_axis=(-1.0, 0.0, 0.0)))
element("IfcColumn", 8, at=column_8_placement, inside=storey, material=ifc_material, Name="Bar#5", ObjectType="Bar#5", context=model_context, shape_type="Clipping", body=[
    clip(clip(extrude(circle(Radius=6.0, at=origin_2d()), origin(), (0.0, 0.0, -1.0), 116.970562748), halfspace(frame((9012.913402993, 6736.736257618, -8.486281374), z_axis=(0.0, 0.0, -1.0), x_axis=(1.0, 0.0, 0.0)), True)), halfspace(frame((9012.913402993, 6736.736257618, -108.484281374), z_axis=(0.0, 0.0, 1.0), x_axis=(-1.0, 0.0, 0.0)), True)),
])
for number, where, z_axis, x_axis, name in (
    (9, (9021.713402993, 6736.736257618, 9675.723292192), (0.0, 0.0, 1.0), (0.0, -1.0, 0.0), "Railing_Post_Landing#5"),
    (10, (9021.713402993, 6736.736257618, 12305.223292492), (0.0, 0.0, 1.0), (0.0, -1.0, 0.0), "Railing_Post_Landing#5"),
):
    element("IfcColumn", number, at=place(None, frame(where, z_axis=z_axis, x_axis=x_axis)), inside=storey, material=ifc_material, Name=name, ObjectType="Railing_Post_Landing#5", context=model_context, shape_type="Clipping", body=[
        clip(clip(extrude(rectangle(XDim=15.0, YDim=60.0, at=origin_2d()), origin(), (0.0, 0.0, -1.0), 1070.646584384), halfspace(frame((6736.736257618, -9021.713402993, -1019.722292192), z_axis=(0.0, 0.0, 1.0), x_axis=(0.0, 1.0, 0.0)), True)), halfspace(frame((6736.736257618, -9021.713402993, -30.924292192), z_axis=(0.0, 0.0, -1.0), x_axis=(0.0, -1.0, 0.0)), True)),
    ])
column_9_placement = place(None, frame((9021.713402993, 7229.236329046, 12287.785281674), z_axis=(0.0, 0.0, 1.0), x_axis=(0.0, -1.0, 0.0)))
element("IfcColumn", 11, at=column_9_placement, inside=storey, material=ifc_material, Name="Railing_Picket_Landing#31", ObjectType="Railing_Picket_Landing#31", context=model_context, shape_type="Clipping", body=[
    clip(clip(extrude(circle(Radius=6.0, at=origin_2d()), origin(), (0.0, 0.0, -1.0), 965.770562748), halfspace(frame((7229.236329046, -9021.713402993, -13.486281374), z_axis=(0.0, 0.0, -1.0), x_axis=(0.0, -1.0, 0.0)), True)), halfspace(frame((7229.236329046, -9021.713402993, -952.284281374), z_axis=(0.0, 0.0, 1.0), x_axis=(0.0, 1.0, 0.0)), True)),
])
column_10_placement = place(None, frame((9021.713402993, 7106.486305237, 12287.785281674), z_axis=(0.0, 0.0, 1.0), x_axis=(0.0, -1.0, 0.0)))
element("IfcColumn", 12, at=column_10_placement, inside=storey, material=ifc_material, Name="Railing_Picket_Landing#32", ObjectType="Railing_Picket_Landing#32", context=model_context, shape_type="Clipping", body=[
    clip(clip(extrude(circle(Radius=6.0, at=origin_2d()), origin(), (0.0, 0.0, -1.0), 965.770562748), halfspace(frame((7106.486305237, -9021.713402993, -13.486281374), z_axis=(0.0, 0.0, -1.0), x_axis=(0.0, -1.0, 0.0)), True)), halfspace(frame((7106.486305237, -9021.713402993, -952.284281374), z_axis=(0.0, 0.0, 1.0), x_axis=(0.0, 1.0, 0.0)), True)),
])
column_11_placement = place(None, frame((9021.713402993, 6983.736281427, 12287.785281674), z_axis=(0.0, 0.0, 1.0), x_axis=(0.0, -1.0, 0.0)))
element("IfcColumn", 13, at=column_11_placement, inside=storey, material=ifc_material, Name="Railing_Picket_Landing#33", ObjectType="Railing_Picket_Landing#33", context=model_context, shape_type="Clipping", body=[
    clip(clip(extrude(circle(Radius=6.0, at=origin_2d()), origin(), (0.0, 0.0, -1.0), 965.770562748), halfspace(frame((6983.736281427, -9021.713402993, -13.486281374), z_axis=(0.0, 0.0, -1.0), x_axis=(0.0, -1.0, 0.0)), True)), halfspace(frame((6983.736281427, -9021.713402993, -952.284281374), z_axis=(0.0, 0.0, 1.0), x_axis=(0.0, 1.0, 0.0)), True)),
])
column_12_placement = place(None, frame((9021.713402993, 6860.986257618, 12287.785281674), z_axis=(0.0, 0.0, 1.0), x_axis=(0.0, -1.0, 0.0)))
element("IfcColumn", 14, at=column_12_placement, inside=storey, material=ifc_material, Name="Railing_Picket_Landing#34", ObjectType="Railing_Picket_Landing#34", context=model_context, shape_type="Clipping", body=[
    clip(clip(extrude(circle(Radius=6.0, at=origin_2d()), origin(), (0.0, 0.0, -1.0), 965.770562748), halfspace(frame((6860.986257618, -9021.713402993, -13.486281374), z_axis=(0.0, 0.0, -1.0), x_axis=(0.0, -1.0, 0.0)), True)), halfspace(frame((6860.986257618, -9021.713402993, -952.284281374), z_axis=(0.0, 0.0, 1.0), x_axis=(0.0, 1.0, 0.0)), True)),
])
column_13_placement = place(None, frame((9021.713402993, 6612.486257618, 12287.785281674), z_axis=(0.0, 0.0, 1.0), x_axis=(0.0, -1.0, 0.0)))
element("IfcColumn", 15, at=column_13_placement, inside=storey, material=ifc_material, Name="Railing_Picket_Landing#35", ObjectType="Railing_Picket_Landing#35", context=model_context, shape_type="Clipping", body=[
    clip(clip(extrude(circle(Radius=6.0, at=origin_2d()), origin(), (0.0, 0.0, -1.0), 965.770562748), halfspace(frame((6612.486257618, -9021.713402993, -13.486281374), z_axis=(0.0, 0.0, -1.0), x_axis=(0.0, -1.0, 0.0)), True)), halfspace(frame((6612.486257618, -9021.713402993, -952.284281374), z_axis=(0.0, 0.0, 1.0), x_axis=(0.0, 1.0, 0.0)), True)),
])
column_14_placement = place(None, frame((9021.713402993, 6489.736233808, 12287.785281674), z_axis=(0.0, 0.0, 1.0), x_axis=(0.0, -1.0, 0.0)))
element("IfcColumn", 16, at=column_14_placement, inside=storey, material=ifc_material, Name="Railing_Picket_Landing#36", ObjectType="Railing_Picket_Landing#36", context=model_context, shape_type="Clipping", body=[
    clip(clip(extrude(circle(Radius=6.0, at=origin_2d()), origin(), (0.0, 0.0, -1.0), 965.770562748), halfspace(frame((6489.736233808, -9021.713402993, -13.486281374), z_axis=(0.0, 0.0, -1.0), x_axis=(0.0, -1.0, 0.0)), True)), halfspace(frame((6489.736233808, -9021.713402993, -952.284281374), z_axis=(0.0, 0.0, 1.0), x_axis=(0.0, 1.0, 0.0)), True)),
])
column_15_placement = place(None, frame((9021.713402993, 6366.986209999, 12287.785281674), z_axis=(0.0, 0.0, 1.0), x_axis=(0.0, -1.0, 0.0)))
element("IfcColumn", 17, at=column_15_placement, inside=storey, material=ifc_material, Name="Railing_Picket_Landing#37", ObjectType="Railing_Picket_Landing#37", context=model_context, shape_type="Clipping", body=[
    clip(clip(extrude(circle(Radius=6.0, at=origin_2d()), origin(), (0.0, 0.0, -1.0), 965.770562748), halfspace(frame((6366.986209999, -9021.713402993, -13.486281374), z_axis=(0.0, 0.0, -1.0), x_axis=(0.0, -1.0, 0.0)), True)), halfspace(frame((6366.986209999, -9021.713402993, -952.284281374), z_axis=(0.0, 0.0, 1.0), x_axis=(0.0, 1.0, 0.0)), True)),
])
column_16_placement = place(None, frame((9012.913402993, 6736.736257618, 12392.785281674), z_axis=(0.0, 0.0, 1.0), x_axis=(-1.0, 0.0, 0.0)))
element("IfcColumn", 18, at=column_16_placement, inside=storey, material=ifc_material, Name="Bar#5", ObjectType="Bar#5", context=model_context, shape_type="Clipping", body=[
    clip(clip(extrude(circle(Radius=6.0, at=origin_2d()), origin(), (0.0, 0.0, -1.0), 116.970562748), halfspace(frame((9012.913402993, 6736.736257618, -8.486281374), z_axis=(0.0, 0.0, -1.0), x_axis=(1.0, 0.0, 0.0)), True)), halfspace(frame((9012.913402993, 6736.736257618, -108.484281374), z_axis=(0.0, 0.0, 1.0), x_axis=(-1.0, 0.0, 0.0)), True)),
])

save(model, "model.ifc")
